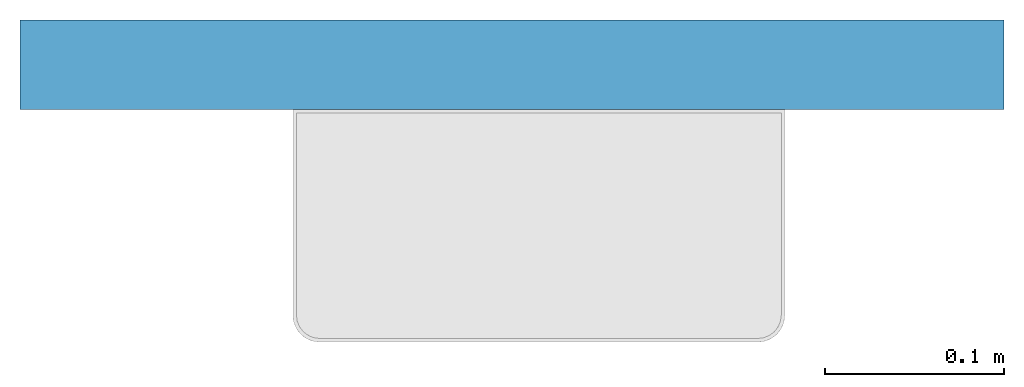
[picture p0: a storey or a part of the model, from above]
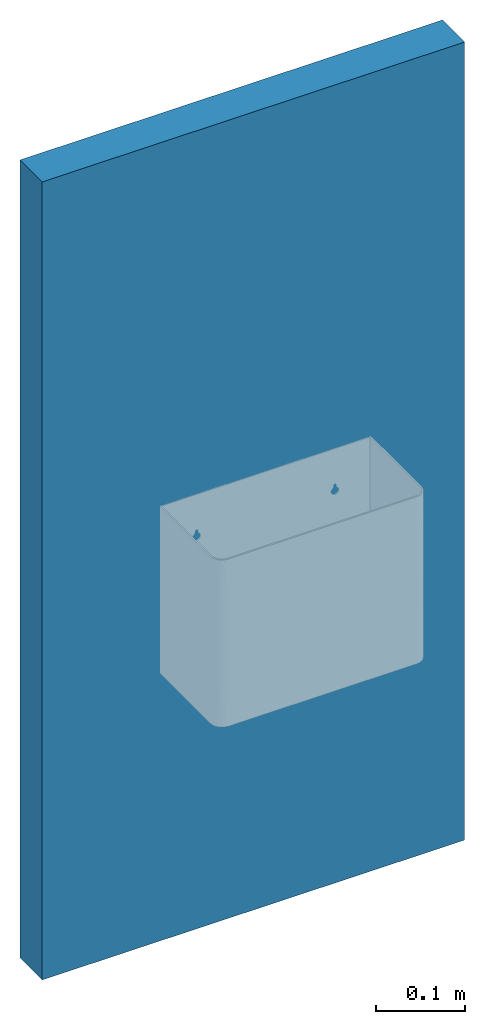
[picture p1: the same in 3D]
Properties of the parts of a building model (IFC2X3)

# File
Description: ViewDefinition [CoordinationView]
Time: 2018-05-30T15:41:25
Written by: The EXPRESS Data Manager Version 5.01.0100.02.64mod : 6 Jun 2012
Made in: 20140709_2115(x64) - Exporter 2014.0.2014.0709 - Default UI
Comment: STEP Physical File produced by: The EXPRESS Data Manager Version 5.01.0100.02.64mod : 6 Jun 2012 * Module: EDMstepFileFactory/EDMstandAlone * Creation date: Wed May 30 15:41:25 2018 * Host: BIM-HP * Database: C:\Users\dcole\AppData\Local\Temp\{5E1D0128-E0C4-4107-8BC1-F384BB4EFFF3}\ifc * Database version: 5507 * Database creation date: Wed May 30 15:41:25 2018 * Schema: IFC2X3 * Model: DataRepository.ifc * Model creation date: Wed May 30 15:41:25 2018 * Header model: DataRepository.ifc_HeaderModel * Header model creation date: Wed May 30 15:41:25 2018 * EDMuser: sdai-user * EDMgroup: sdai-group * License ID and type: 5605 : Permanent license. Expiry date: * EDMstepFileFactory options: 020000

# IfcProject
LongName: P:\Fastrack\53721_DOLPHIN SOLUTIONS LIMITED\ADDITIONAL DRAWINGS 2018 BIM\IFC\BC922.ifc

# IfcSite, Default
RefLatitude: 42, 24, 53, 508911; RefLongitude: -71, -15, -29, -58837; RefElevation: 0 mm

# IfcBuilding
Pset_BuildingCommon - NumberOfStoreys: 1

# IfcBuildingStorey, Level 1
LongName: Level 1; Elevation: 0 mm
Constraints - Elevation Base: Project Base Point; Elevation: 0 mm
Identity Data - Structural: no; Building Story: yes; Name: Level 1
Dimensions - Computation Height: 0 mm
Graphics - Symbol at End 2 Default: yes; Color: 0; Line Weight: 1; Symbol at End 1 Default: no; Line Pattern: -3000010

# IfcBuildingElementProxy: BC922 Dolphin Stainless Steel Surface Mounted Bin, BC922:BC922 Dolphin Stainless Steel Surface Mounted Bin:98771
In: Level 1
Material: Stainless Steel
Constraints - Level: Level: Level 1; Offset: 375.254 mm; Host: Level : Level 1; Moves With Nearby Elements: no
Phasing - Phase Created: New Construction
Dimensions - Volume: 0.0005373 m3; Width: 275mm; Projection: 130mm; Height: 230mm
Pset_ManufacturerTypeInformation - Manufacturer: Dolphin Solutions Ltd.
Pset_BuildingElementProxyCommon - Reference: BC922 Dolphin Stainless Steel Surface Mounted Bin
Identity Data - Type Comments: Wire bin for this product = BC921-1; Email: info@dolphinsolutions.co.uk; Model: BC922; Tel No.: +44 (0) 1424 202 224; Manufacturer: Dolphin Solutions Ltd.; Description: Stainless steel surface mounted bin; Assembly Description: Other Plumbing Fixtures; Fax No.: +44 (0) 1424 205 200; Address: Southpoint, Compass Park, Junction Road, Bodiam, TN32 5BS; Assembly Code: D2010900; URL: www.dolphinsolutions.co.uk
General - Product Page Link: https://www.dolphinsolutions.co.uk/product/stainless-steel-surface-mounted-bin/; Capacity Bin: 8 litre; Product Data: High quality satin stainless steel. Wall mounted. Open top. 8 litre capacity.

# IfcWallStandardCase: Basic Wall:Wall 1, Basic Wall:Wall 1:3092
In: Level 1
Type - PredefinedType: STANDARD; Material: Default Wall 50 mm
Type - Graphics - Coarse Scale Fill Color: 8454143
Type - Construction - Wrapping at Inserts: Do not wrap; Width: 50 mm; Function: Exterior
Type - Analytical Properties - Roughness: 1; Absorptance: 0.1
Constraints - Base Extension Distance: 0 mm; Top Extension Distance: 0 mm; Related to Mass: no; Unconnected Height: 1098.33 mm; Base Offset: 5.7608 mm; Top is Attached: no; Base Constraint: Level: Level 1; Room Bounding: yes; Location Line: Finish Face: Interior; Base is Attached: no; Top Offset: 0 mm
Dimensions - Area: 0.604082 m2; Volume: 0.0302041 m3; Length: 550 mm
Phasing - Phase Created: New Construction
Structural - Structural Usage: Non-bearing; Structural: no; Enable Analytical Model: no
Pset_WallCommon - Reference: Wall 1; LoadBearing: no; ExtendToStructure: no; IsExternal: yes
